One B-rep face of a CAD part: STEP entity #50598.
In plain terms, the planar face has unit normal (0, 0, 1).
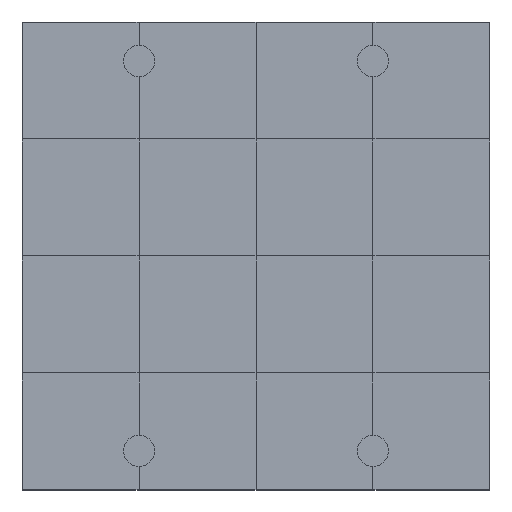
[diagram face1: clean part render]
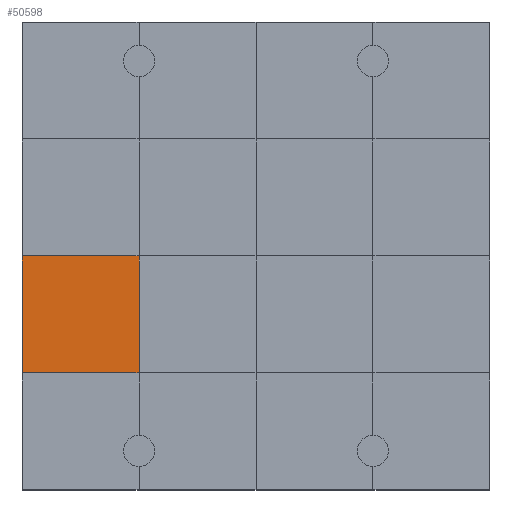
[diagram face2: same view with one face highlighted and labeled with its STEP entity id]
Its self-contained STEP definition (entity closure, numbers rounded to 3 decimals):
#50148 = VERTEX_POINT('',#50149);
#50149 = CARTESIAN_POINT('',(0.,3.,1.2));
#50163 = PLANE('',#50164);
#50164 = AXIS2_PLACEMENT_3D('',#50165,#50166,#50167);
#50165 = CARTESIAN_POINT('',(0.,3.,0.));
#50166 = DIRECTION('',(1.,0.,-0.));
#50167 = DIRECTION('',(0.,0.,1.));
#50189 = PLANE('',#50190);
#50190 = AXIS2_PLACEMENT_3D('',#50191,#50192,#50193);
#50191 = CARTESIAN_POINT('',(0.,0.,1.2));
#50192 = DIRECTION('',(0.,0.,1.));
#50193 = DIRECTION('',(1.,0.,-0.));
#50340 = VERTEX_POINT('',#50341);
#50341 = CARTESIAN_POINT('',(3.,3.,1.2));
#50362 = EDGE_CURVE('',#50148,#50340,#50363,.T.);
#50363 = SURFACE_CURVE('',#50364,(#50368,#50375),.PCURVE_S1.);
#50364 = LINE('',#50365,#50366);
#50365 = CARTESIAN_POINT('',(0.,3.,1.2));
#50366 = VECTOR('',#50367,1.);
#50367 = DIRECTION('',(1.,0.,-0.));
#50368 = PCURVE('',#50189,#50369);
#50369 = DEFINITIONAL_REPRESENTATION('',(#50370),#50374);
#50370 = LINE('',#50371,#50372);
#50371 = CARTESIAN_POINT('',(0.,3.));
#50372 = VECTOR('',#50373,1.);
#50373 = DIRECTION('',(1.,0.));
#50374 = ( GEOMETRIC_REPRESENTATION_CONTEXT(2) 
PARAMETRIC_REPRESENTATION_CONTEXT() REPRESENTATION_CONTEXT('2D SPACE',''
  ) );
#50375 = PCURVE('',#50376,#50381);
#50376 = PLANE('',#50377);
#50377 = AXIS2_PLACEMENT_3D('',#50378,#50379,#50380);
#50378 = CARTESIAN_POINT('',(0.,3.,1.2));
#50379 = DIRECTION('',(0.,0.,1.));
#50380 = DIRECTION('',(1.,0.,-0.));
#50381 = DEFINITIONAL_REPRESENTATION('',(#50382),#50386);
#50382 = LINE('',#50383,#50384);
#50383 = CARTESIAN_POINT('',(0.,0.));
#50384 = VECTOR('',#50385,1.);
#50385 = DIRECTION('',(1.,0.));
#50386 = ( GEOMETRIC_REPRESENTATION_CONTEXT(2) 
PARAMETRIC_REPRESENTATION_CONTEXT() REPRESENTATION_CONTEXT('2D SPACE',''
  ) );
#50421 = VERTEX_POINT('',#50422);
#50422 = CARTESIAN_POINT('',(0.,6.,1.2));
#50448 = EDGE_CURVE('',#50148,#50421,#50449,.T.);
#50449 = SURFACE_CURVE('',#50450,(#50454,#50461),.PCURVE_S1.);
#50450 = LINE('',#50451,#50452);
#50451 = CARTESIAN_POINT('',(0.,3.,1.2));
#50452 = VECTOR('',#50453,1.);
#50453 = DIRECTION('',(-0.,1.,0.));
#50454 = PCURVE('',#50163,#50455);
#50455 = DEFINITIONAL_REPRESENTATION('',(#50456),#50460);
#50456 = LINE('',#50457,#50458);
#50457 = CARTESIAN_POINT('',(1.2,0.));
#50458 = VECTOR('',#50459,1.);
#50459 = DIRECTION('',(0.,-1.));
#50460 = ( GEOMETRIC_REPRESENTATION_CONTEXT(2) 
PARAMETRIC_REPRESENTATION_CONTEXT() REPRESENTATION_CONTEXT('2D SPACE',''
  ) );
#50461 = PCURVE('',#50376,#50462);
#50462 = DEFINITIONAL_REPRESENTATION('',(#50463),#50467);
#50463 = LINE('',#50464,#50465);
#50464 = CARTESIAN_POINT('',(0.,0.));
#50465 = VECTOR('',#50466,1.);
#50466 = DIRECTION('',(0.,1.));
#50467 = ( GEOMETRIC_REPRESENTATION_CONTEXT(2) 
PARAMETRIC_REPRESENTATION_CONTEXT() REPRESENTATION_CONTEXT('2D SPACE',''
  ) );
#50598 = ADVANCED_FACE('',(#50599),#50376,.T.);
#50599 = FACE_BOUND('',#50600,.T.);
#50600 = EDGE_LOOP('',(#50601,#50602,#50603,#50631));
#50601 = ORIENTED_EDGE('',*,*,#50448,.F.);
#50602 = ORIENTED_EDGE('',*,*,#50362,.T.);
#50603 = ORIENTED_EDGE('',*,*,#50604,.T.);
#50604 = EDGE_CURVE('',#50340,#50605,#50607,.T.);
#50605 = VERTEX_POINT('',#50606);
#50606 = CARTESIAN_POINT('',(3.,6.,1.2));
#50607 = SURFACE_CURVE('',#50608,(#50612,#50619),.PCURVE_S1.);
#50608 = LINE('',#50609,#50610);
#50609 = CARTESIAN_POINT('',(3.,3.,1.2));
#50610 = VECTOR('',#50611,1.);
#50611 = DIRECTION('',(-0.,1.,0.));
#50612 = PCURVE('',#50376,#50613);
#50613 = DEFINITIONAL_REPRESENTATION('',(#50614),#50618);
#50614 = LINE('',#50615,#50616);
#50615 = CARTESIAN_POINT('',(3.,0.));
#50616 = VECTOR('',#50617,1.);
#50617 = DIRECTION('',(0.,1.));
#50618 = ( GEOMETRIC_REPRESENTATION_CONTEXT(2) 
PARAMETRIC_REPRESENTATION_CONTEXT() REPRESENTATION_CONTEXT('2D SPACE',''
  ) );
#50619 = PCURVE('',#50620,#50625);
#50620 = PLANE('',#50621);
#50621 = AXIS2_PLACEMENT_3D('',#50622,#50623,#50624);
#50622 = CARTESIAN_POINT('',(3.,3.,1.2));
#50623 = DIRECTION('',(0.,0.,1.));
#50624 = DIRECTION('',(1.,0.,-0.));
#50625 = DEFINITIONAL_REPRESENTATION('',(#50626),#50630);
#50626 = LINE('',#50627,#50628);
#50627 = CARTESIAN_POINT('',(0.,0.));
#50628 = VECTOR('',#50629,1.);
#50629 = DIRECTION('',(0.,1.));
#50630 = ( GEOMETRIC_REPRESENTATION_CONTEXT(2) 
PARAMETRIC_REPRESENTATION_CONTEXT() REPRESENTATION_CONTEXT('2D SPACE',''
  ) );
#50631 = ORIENTED_EDGE('',*,*,#50632,.F.);
#50632 = EDGE_CURVE('',#50421,#50605,#50633,.T.);
#50633 = SURFACE_CURVE('',#50634,(#50638,#50645),.PCURVE_S1.);
#50634 = LINE('',#50635,#50636);
#50635 = CARTESIAN_POINT('',(0.,6.,1.2));
#50636 = VECTOR('',#50637,1.);
#50637 = DIRECTION('',(1.,0.,-0.));
#50638 = PCURVE('',#50376,#50639);
#50639 = DEFINITIONAL_REPRESENTATION('',(#50640),#50644);
#50640 = LINE('',#50641,#50642);
#50641 = CARTESIAN_POINT('',(0.,3.));
#50642 = VECTOR('',#50643,1.);
#50643 = DIRECTION('',(1.,0.));
#50644 = ( GEOMETRIC_REPRESENTATION_CONTEXT(2) 
PARAMETRIC_REPRESENTATION_CONTEXT() REPRESENTATION_CONTEXT('2D SPACE',''
  ) );
#50645 = PCURVE('',#50646,#50651);
#50646 = PLANE('',#50647);
#50647 = AXIS2_PLACEMENT_3D('',#50648,#50649,#50650);
#50648 = CARTESIAN_POINT('',(0.,6.,1.2));
#50649 = DIRECTION('',(0.,0.,1.));
#50650 = DIRECTION('',(1.,0.,-0.));
#50651 = DEFINITIONAL_REPRESENTATION('',(#50652),#50656);
#50652 = LINE('',#50653,#50654);
#50653 = CARTESIAN_POINT('',(0.,0.));
#50654 = VECTOR('',#50655,1.);
#50655 = DIRECTION('',(1.,0.));
#50656 = ( GEOMETRIC_REPRESENTATION_CONTEXT(2) 
PARAMETRIC_REPRESENTATION_CONTEXT() REPRESENTATION_CONTEXT('2D SPACE',''
  ) );
